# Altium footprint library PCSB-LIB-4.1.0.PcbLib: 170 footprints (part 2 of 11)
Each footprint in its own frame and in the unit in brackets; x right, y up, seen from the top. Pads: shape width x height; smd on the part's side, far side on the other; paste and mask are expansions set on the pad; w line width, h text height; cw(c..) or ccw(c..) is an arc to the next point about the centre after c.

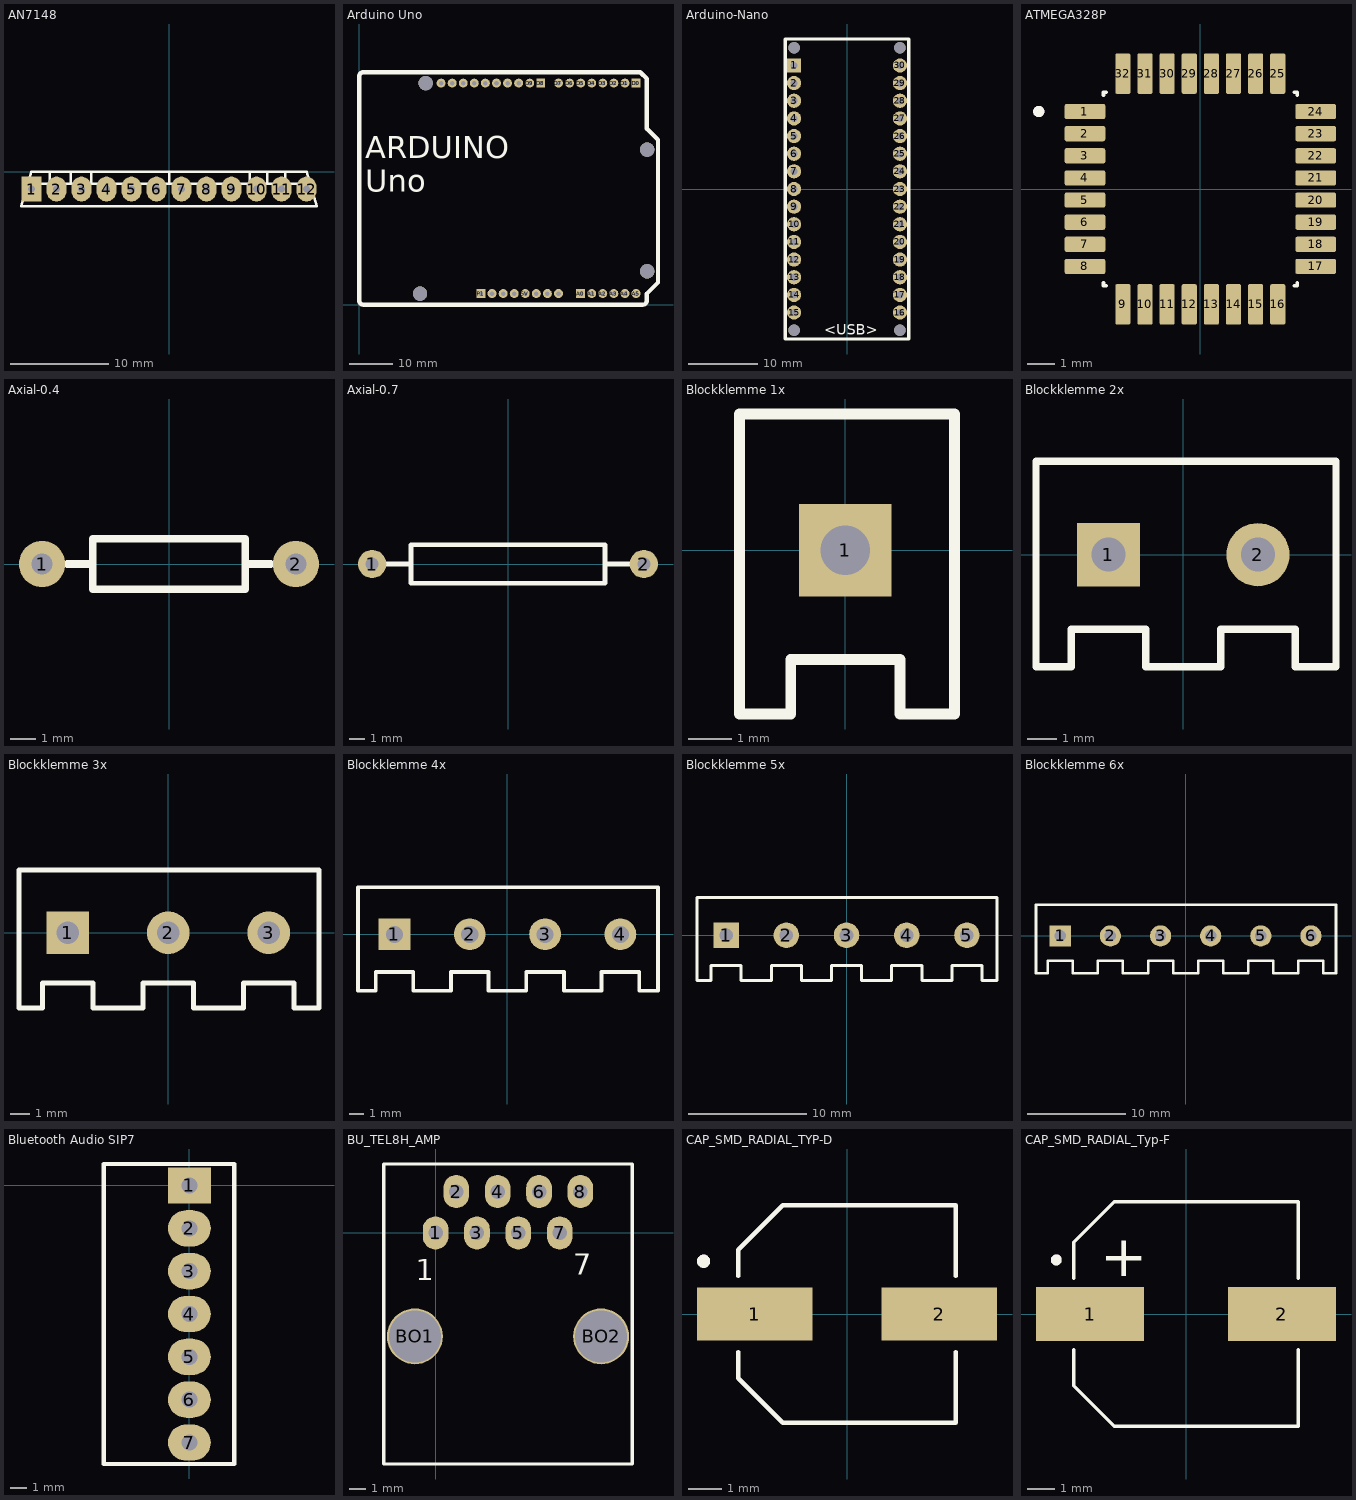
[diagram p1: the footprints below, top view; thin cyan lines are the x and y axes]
## AN7148 [mm]
pads (12):
  rect 2x2.54 hole 0.75: 1(-13.97,-1.753)
  oval 2x2.54 hole 0.75: 2(-11.43,-1.753) 3(-8.89,-1.753) 4(-6.35,-1.753) 5(-3.81,-1.753) 6(-1.27,-1.753) 7(1.27,-1.753) 8(3.81,-1.753) 9(6.35,-1.753) 10(8.89,-1.753) 11(11.43,-1.753) 12(13.97,-1.753)
Top Overlay:
  lines w0.254: -14.343,-1.2 14.343,-1.2 ; -12.1,-1.2 -12.1,0 ; -10,-1.2 -10,0 ; -7.9,-1.2 -7.9,0 ; 0,-1.2 0,0 ; 8.2,-1.2 8.2,0 ; 10,-1.2 10,0 ; 11.8,-1.2 11.8,0 ; -15,-3.5 15,-3.5 14,0 -14,0 -15,-3.5

## Arduino Uno [mm]
pads (36):
  round 2.05 hole 1.05: 3V3(35.56,2.54) 5V(38.1,2.54) A1(53.34,2.54) A2(55.88,2.54) A3(58.42,2.54) A4(60.96,2.54) A4(SDA)(21.336,50.8) A5(63.5,2.54) A5(SCL)(18.796,50.8) AREF(23.876,50.8) D1(60.96,50.8) D2(58.42,50.8) D3(55.88,50.8) D4(53.34,50.8) D5(50.8,50.8) D6(48.26,50.8) D7(45.72,50.8) D9(39.116,50.8) D10(36.576,50.8) D11(34.036,50.8) D12(31.496,50.8) D13(28.956,50.8) GND_1(43.18,2.54) GND_2(40.64,2.54) GND_3(26.416,50.8) IOREF(30.48,2.54) RST(33.02,2.54) VIN(45.72,2.54)
  rect 2.05x2.05 hole 1.05: A0(50.8,2.54) D0(63.5,50.8) D8(41.656,50.8) P1(27.94,2.54)
  round 3.3 hole 3.3 unplated: ""(13.97,2.54) ""(15.24,50.8) ""(66.04,7.62) ""(66.04,35.56)
Top Overlay:
  lines w1: 0,0.993 0,52.283 ; 0,0.993 0.042,0.739 ; 0,0.993 0.042,0.739 ; 0,0.993 0,52.283 ; 0,52.283 0.042,52.558 ; 0,52.283 0.042,52.558 ; 0.042,0.739 0.127,0.506 ; 0.042,0.739 0.127,0.506 ; 0.042,52.558 0.127,52.791 ; 0.042,52.558 0.127,52.791 ; 0.127,0.506 0.296,0.295 ; 0.127,0.506 0.296,0.295 ; 0.127,52.791 0.296,53.002 ; 0.127,52.791 0.296,53.002 ; 0.296,0.295 0.508,0.126 ; 0.296,0.295 0.508,0.126 ; 0.296,53.002 0.508,53.151 ; 0.296,53.002 0.508,53.151 ; 0.508,0.126 0.741,0.041 ; 0.508,0.126 0.741,0.041 ; 0.508,53.151 0.741,53.256 ; 0.508,53.151 0.741,53.256 ; 0.741,0.041 0.994,-0.001 ; 0.741,0.041 0.994,-0.001 ; 0.741,53.256 0.994,53.299 ; 0.741,53.256 0.994,53.299 ; 0.994,-0.001 65.001,-0.001 ; 0.994,-0.001 65.001,-0.001 ; 0.994,53.299 64.472,53.299 ; 0.994,53.299 64.472,53.299 ; 64.472,53.299 65.995,51.775 ; 64.472,53.299 65.995,51.775 ; 65.001,-0.001 65.255,0.041 ; 65.001,-0.001 65.255,0.041 ; 65.255,0.041 65.488,0.126 ; 65.255,0.041 65.488,0.126 ; 65.488,0.126 65.699,0.295 ; 65.488,0.126 65.699,0.295 ; 65.699,0.295 65.869,0.506 ; 65.699,0.295 65.869,0.506 ; 65.869,0.506 65.953,0.739 ; 65.869,0.506 65.953,0.739 ; 65.953,0.739 65.995,0.993 ; 65.953,0.739 65.995,0.993 ; 65.995,0.993 65.995,2.538 ; 65.995,0.993 65.995,2.538 ; 65.995,2.538 68.535,5.077 ; 65.995,2.538 68.535,5.077 ; 65.995,40.349 68.535,37.81 ; 65.995,40.349 65.995,51.775 ; 65.995,40.349 65.995,51.775 ; 65.995,40.349 68.535,37.81 ; 68.535,5.077 68.535,37.81 ; 68.535,5.077 68.535,37.81
  text "ARDUINO  / Uno" at 1.397,25.913 h5.08
Mechanical 15:
  lines w0.05: -0.25,1.003 ccw(c0.932,0.921) 0.747,-0.249 ; 64.989,-0.25 ccw(c64.943,1.057) 66.249,0.989

## Arduino-Nano [mm]
pads (34):
  rect 2.05x2.05 hole 1.05: 1(-7.62,17.78)
  round 2.05 hole 1.05: 2(-7.62,15.24) 3(-7.62,12.7) 4(-7.62,10.16) 5(-7.62,7.62) 6(-7.62,5.08) 7(-7.62,2.54) 8(-7.62,0) 9(-7.62,-2.54) 10(-7.62,-5.08) 11(-7.62,-7.62) 12(-7.62,-10.16) 13(-7.62,-12.7) 14(-7.62,-15.24) 15(-7.62,-17.78) 16(7.62,-17.78) 17(7.62,-15.24) 18(7.62,-12.7) 19(7.62,-10.16) 20(7.62,-7.62) 21(7.62,-5.08) 22(7.62,-2.54) 23(7.62,0) 24(7.62,2.54) 25(7.62,5.08) 26(7.62,7.62) 27(7.62,10.16) 28(7.62,12.7) 29(7.62,15.24) 30(7.62,17.78)
  round 1.651 hole 1.651 unplated: ""(-7.62,-20.32) ""(-7.62,20.32) ""(7.62,-20.32) ""(7.62,20.32)
Top Overlay:
  lines w0.5: -8.89,-21.59 8.89,-21.59 8.89,21.59 -8.89,21.59 -8.89,-21.59
  text "<USB>" at -3.302,-20.955 h1.52

## ATMEGA328P [mm]
height 1.2
pads (32):
  rrect25% 1.47x0.55 smd: 1(-4.17,2.8) 2(-4.17,2) 3(-4.17,1.2) 4(-4.17,0.4) 5(-4.17,-0.4) 6(-4.17,-1.2) 7(-4.17,-2) 8(-4.17,-2.8) 17(4.17,-2.8) 18(4.17,-2) 19(4.17,-1.2) 20(4.17,-0.4) 21(4.17,0.4) 22(4.17,1.2) 23(4.17,2) 24(4.17,2.8)
  rrect25% 0.55x1.47 smd: 9(-2.8,-4.17) 10(-2,-4.17) 11(-1.2,-4.17) 12(-0.4,-4.17) 13(0.4,-4.17) 14(1.2,-4.17) 15(2,-4.17) 16(2.8,-4.17) 25(2.8,4.17) 26(2,4.17) 27(1.2,4.17) 28(0.4,4.17) 29(-0.4,4.17) 30(-1.2,4.17) 31(-2,4.17) 32(-2.8,4.17)
Top Overlay:
  circle w0.2: c-5.84,2.8 r0.1
  lines w0.127: -3.5,-3.395 -3.5,-3.5 -3.395,-3.5 ; -3.5,3.395 -3.5,3.5 -3.395,3.5 ; 3.395,-3.5 3.5,-3.5 3.5,-3.395 ; 3.395,3.5 3.5,3.5 3.5,3.395
Mechanical 13:
  circle w0.2: c-5.84,2.8 r0.1

## Axial-0.4 [mm]
pads (2):
  round 1.85 hole 0.85: 1(-5.08,0) 2(5.08,0)
Top Overlay:
  lines w0.305: -4.064,0 -3.048,0 ; 3.048,0 4.064,0 ; -3.048,-1.016 -3.048,1.016 3.048,1.016 3.048,-1.016 -3.048,-1.016

## Axial-0.7 [mm]
pads (2):
  round 1.85 hole 0.85: 1(-8.89,0) 2(8.89,0)
Top Overlay:
  lines w0.305: -8.89,0 -6.35,0 ; 6.35,0 8.89,0 ; -6.35,-1.27 6.35,-1.27 6.35,1.27 -6.35,1.27 -6.35,-1.27

## Blockklemme 1x [mm]
pads (1):
  rect 2.15x2.15 hole 1.15: 1(0,0)
Top Overlay:
  lines w0.254: -2.46,-3.81 -2.46,2.365 -2.46,3.175 2.54,3.175 2.54,-3.81 1.27,-3.81 1.27,-2.54 -1.27,-2.54 -1.27,-3.81 -2.46,-3.81

## Blockklemme 2x [mm]
pads (2):
  rect 2.15x2.15 hole 1.15: 1(-2.54,0)
  round 2.15 hole 1.15: 2(2.54,0)
Top Overlay:
  lines w0.254: 1.27,-3.81 1.27,-2.54 ; 1.27,-3.81 -1.27,-3.81 -1.27,-2.54 -3.81,-2.54 -3.81,-3.81 -5,-3.81 -5,2.365 -5,3.175 5.19,3.175 5.19,-3.81 3.81,-3.81 ; 1.27,-3.81 1.27,-2.54 ; 1.27,-2.54 3.81,-2.54 ; 3.81,-3.81 3.81,-2.54 ; 3.81,-3.81 3.81,-2.54

## Blockklemme 3x [mm]
pads (3):
  rect 2.15x2.15 hole 1.15: 1(-5.08,0)
  round 2.15 hole 1.15: 2(0,0) 3(5.08,0)
Top Overlay:
  lines w0.254: -1.27,-3.81 -1.27,-2.54 ; -1.27,-3.81 -3.81,-3.81 -3.81,-2.54 -6.35,-2.54 -6.35,-3.81 -7.54,-3.81 -7.54,2.365 -7.54,3.175 2.65,3.175 7.62,3.175 7.62,-3.81 6.35,-3.81 6.35,-2.54 3.81,-2.54 3.81,-3.81 1.27,-3.81 ; -1.27,-3.81 -1.27,-2.54 ; -1.27,-2.54 1.27,-2.54 ; 1.27,-3.81 1.27,-2.54 ; 1.27,-3.81 1.27,-2.54

## Blockklemme 4x [mm]
pads (4):
  rect 2.15x2.15 hole 1.15: 1(-7.62,0)
  round 2.15 hole 1.15: 2(-2.54,0) 3(2.54,0) 4(7.62,0)
Top Overlay:
  lines w0.254: -3.81,-3.81 -3.81,-2.54 ; -3.81,-3.81 -6.35,-3.81 -6.35,-2.54 -8.89,-2.54 -8.89,-3.81 -10.08,-3.81 -10.08,2.365 -10.08,3.175 0.11,3.175 10.16,3.175 10.16,-3.81 8.89,-3.81 8.89,-2.54 6.35,-2.54 6.35,-3.81 3.81,-3.81 3.81,-2.54 1.27,-2.54 1.27,-3.81 -1.27,-3.81 ; -3.81,-3.81 -3.81,-2.54 ; -3.81,-2.54 -1.27,-2.54 ; -1.27,-3.81 -1.27,-2.54 ; -1.27,-3.81 -1.27,-2.54

## Blockklemme 5x [mm]
pads (5):
  rect 2.15x2.15 hole 1.15: 1(-10.16,0)
  round 2.15 hole 1.15: 2(-5.08,0) 3(0,0) 4(5.08,0) 5(10.16,0)
Top Overlay:
  lines w0.254: -6.35,-3.81 -6.35,-2.54 ; -6.35,-3.81 -8.89,-3.81 -8.89,-2.54 -11.43,-2.54 -11.43,-3.81 -12.62,-3.81 -12.62,2.365 -12.62,3.175 -2.43,3.175 12.7,3.175 12.7,-3.81 11.43,-3.81 11.43,-2.54 8.89,-2.54 8.89,-3.81 6.35,-3.81 6.35,-2.54 3.81,-2.54 3.81,-3.81 1.27,-3.81 1.27,-2.54 -1.27,-2.54 -1.27,-3.81 -3.81,-3.81 ; -6.35,-3.81 -6.35,-2.54 ; -6.35,-2.54 -3.81,-2.54 ; -3.81,-3.81 -3.81,-2.54 ; -3.81,-3.81 -3.81,-2.54

## Blockklemme 6x [mm]
pads (6):
  rect 2.15x2.15 hole 1.15: 1(-12.7,0)
  round 2.15 hole 1.15: 2(-7.62,0) 3(-2.54,0) 4(2.54,0) 5(7.62,0) 6(12.7,0)
Top Overlay:
  lines w0.254: -8.89,-3.81 -8.89,-2.54 ; -8.89,-3.81 -11.43,-3.81 -11.43,-2.54 -13.97,-2.54 -13.97,-3.81 -15.16,-3.81 -15.16,2.365 -15.16,3.175 -4.97,3.175 15.24,3.175 15.24,-3.81 13.97,-3.81 13.97,-2.54 11.43,-2.54 11.43,-3.81 8.89,-3.81 8.89,-2.54 6.35,-2.54 6.35,-3.81 3.81,-3.81 3.81,-2.54 1.27,-2.54 1.27,-3.81 -1.27,-3.81 -1.27,-2.54 -3.81,-2.54 -3.81,-3.81 -6.35,-3.81 ; -8.89,-3.81 -8.89,-2.54 ; -8.89,-2.54 -6.35,-2.54 ; -6.35,-3.81 -6.35,-2.54 ; -6.35,-3.81 -6.35,-2.54

## Bluetooth Audio SIP7 [mm]
pads (7):
  rect 2.54x2.15 hole 0.95: 1(0,0)
  oval 2.54x2.15 hole 0.95: 2(0,-2.54) 3(0,-5.08) 4(0,-7.62) 5(0,-10.16) 6(0,-12.7) 7(0,-15.24)
Top Overlay:
  lines w0.254: -5.08,-16.51 2.667,-16.51 2.667,1.27 -5.08,1.27 -5.08,-16.51

## BU_TEL8H_AMP [mil]
pads (10):
  oval 62x80 hole 35: 1(0,0) 2(50,100) 3(100,0) 4(150,100) 5(200,0) 6(250,100) 7(300,0) 8(350,100)
  round 135 hole 125: BO1(-50,-250) BO2(400,-250)
Top Overlay:
  lines w8: -125,-558.33 -125,166.67 475,166.67 475,-558.33 -125,-558.33
  text "1" at -47.84,-114.13 h50
  text "7" at 332.45,-101.06 h50

## CAP_SMD_RADIAL_TYP-D [mm]
pads (2):
  rect 3.5x1.6 smd: 1(-2.8,0) 2(2.8,0)
Top Overlay:
  circle w0.2: c-4.35,1.6 r0.1
  lines w0.127: -3.3,-1.15 -3.3,-1.95 -1.95,-3.3 3.3,-3.3 3.3,-1.15 ; -3.3,1.15 -3.3,1.95 -1.95,3.3 3.3,3.3 3.3,1.15
Mechanical 13:
  circle w0.2: c-4.35,1.6 r0.1

## CAP_SMD_RADIAL_Typ-F [mm]
pads (2):
  rect 4x2 smd: 1(-3.55,0) 2(3.55,0)
Top Overlay:
  circle w0.2: c-4.8,2 r0.1
  lines w0.127: -4.15,-1.32 -4.15,-2.65 -2.65,-4.15 4.15,-4.15 4.15,-1.32 ; -4.15,1.32 -4.15,2.65 -2.65,4.15 4.15,4.15 4.15,1.32
  text "+" at -3.175,1.397 h1.52
Mechanical 13:
  circle w0.2: c-4.8,2 r0.1
3D body "step_temp.STEP": height 0, standoff 0, extent 0,0 0,0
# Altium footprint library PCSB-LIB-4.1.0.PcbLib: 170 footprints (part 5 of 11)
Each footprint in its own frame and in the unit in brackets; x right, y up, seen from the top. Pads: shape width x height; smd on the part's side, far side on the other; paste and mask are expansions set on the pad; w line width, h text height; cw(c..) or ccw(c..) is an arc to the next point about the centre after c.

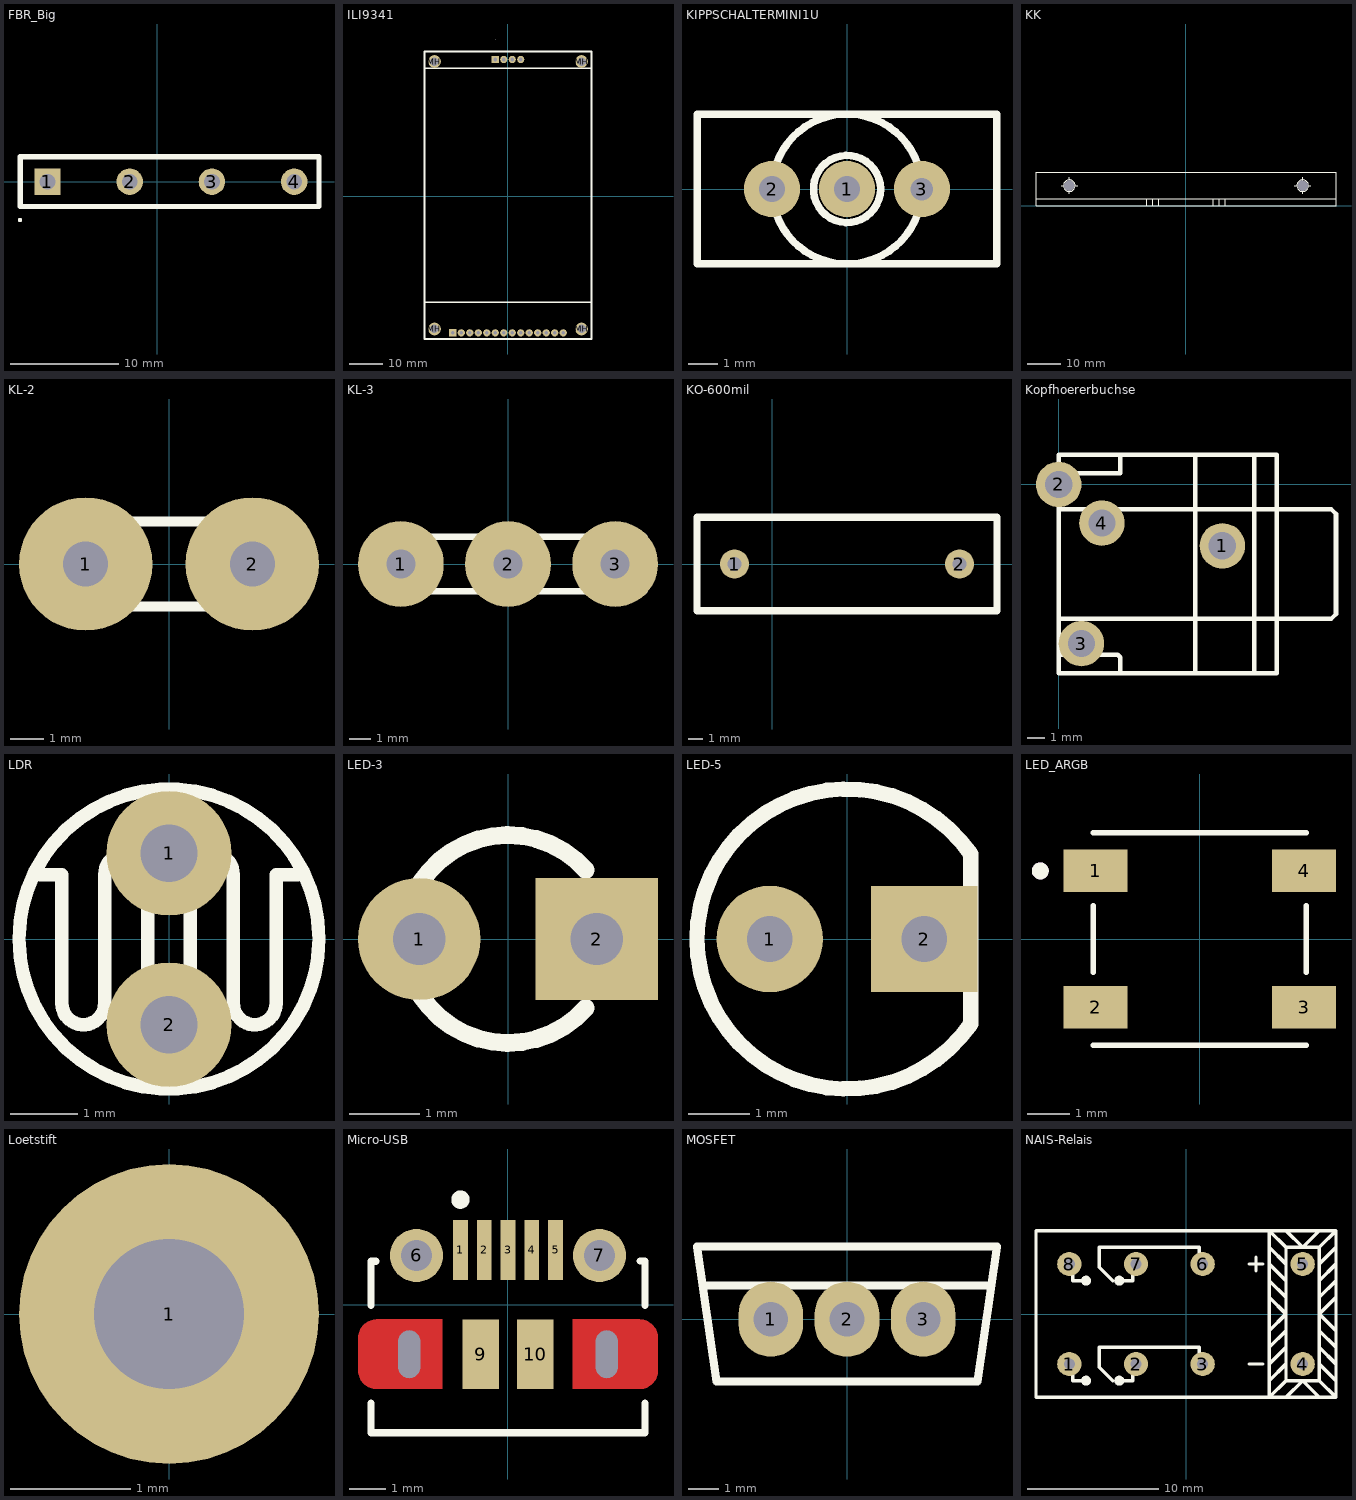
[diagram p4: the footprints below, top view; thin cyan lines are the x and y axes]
## FBR_Big [mm]
height 23
pads (4):
  rect 2.45x2.45 hole 1.45: 1(-10.16,0)
  round 2.45 hole 1.45: 2(-2.54,0) 3(5.08,0) 4(12.7,0)
Top Overlay:
  circle w0.2: c-12.7,-3.556 r0.1
  lines w0.5: -12.7,-2.3 15,-2.3 15,2.3 -12.7,2.3 -12.7,-2.3

## ILI9341 [mm]
pads (22):
  rect 2.15x2.15 hole 1.15: A1(-3.81,40.88) B1(-16.51,-40.88)
  round 2.15 hole 1.15: A2(-1.27,40.88) A3(1.27,40.88) A4(3.81,40.88) B2(-13.97,-40.88) B3(-11.43,-40.88) B4(-8.89,-40.88) B5(-6.35,-40.88) B6(-3.81,-40.88) B7(-1.27,-40.88) B8(1.27,-40.88) B9(3.81,-40.88) B10(6.35,-40.88) B11(8.89,-40.88) B12(11.43,-40.88) B13(13.97,-40.88) B14(16.51,-40.88)
  round 3.81 hole 2.54: MH(-22,-39.73) MH(-22,40.27) MH(22,-39.73) MH(22,40.27)
Top Overlay:
  lines w0.1: -3.81,46.92 cw(c-3.81,46.97) -3.81,47.02 cw(c-3.81,46.97) -3.81,46.92
  lines w0.5: -25,-31.73 25,-31.73 ; -25,38.27 25,38.27 ; -25,-42.73 -25,43.27 25,43.27 25,1.27 25,-42.73 -25,-42.73

## KIPPSCHALTERMINI1U [mil]
pads (3):
  round 75 hole 35: 1(0,0) 2(-100,0)
  round 75 hole 30: 3(100,0)
Top Overlay:
  circle w10: c0,0 r100
  circle w10: c0,0 r44.72
  lines w10: 0,-30 cw(c0,0) 9.49,28.46 ; -200,-100 200,-100 200,100 -200,100 -200,-100

## KK [mm]
pads (2):
  rect 0x0 hole 3.2 unplated: 0(-35,6) 0(35,6)
Top Overlay:
  circle w0.254: c-35,6 r1.75
  circle w0.254: c35,6 r1.75
  lines w0.254: -45,2 45,2 ; -37.5,6 -32.5,6 ; -35,3.5 -35,8.5 ; -11.8,0 -11.8,2 ; -10,0 -10,2 ; -8.2,0 -8.2,2 ; 8.2,0 8.2,2 ; 10,0 10,2 ; 11.8,0 11.8,2 ; 32.5,6 37.5,6 ; 35,3.5 35,8.5 ; -45,0 45,0 45,10 -45,10 -45,0

## KL-2 [mm]
height 10
pads (2):
  round 4 hole 1.35: 1(-2.5,0) 2(2.5,0)
Top Overlay:
  lines w0.3: -3.81,-1.27 -3.81,1.27 3.81,1.27 3.81,-1.27 -3.81,-1.27

## KL-3 [mm]
height 10
pads (3):
  round 4 hole 1.35: 1(-5,0) 2(0,0) 3(5,0)
Top Overlay:
  lines w0.3: -5.715,-1.27 -5.715,1.27 6.35,1.27 6.35,-1.27 -5.715,-1.27

## KO-600mil [mm]
pads (2):
  round 1.95 hole 0.95: 1(-2.54,0) 2(12.7,0)
Top Overlay:
  lines w0.5: -5.08,1.27 -5.08,3.175 15.24,3.175 15.24,-3.175 -5.08,-3.175 -5.08,1.595

## Kopfhoererbuchse [mil]
pads (4):
  round 100 hole 60: 1(360,-135) 2(0,0) 3(50,-350) 4(95,-85)
Top Overlay:
  lines w10: 0,-375 130,-375 135,-380 135,-415 ; 0,-295 480,-295 600,-295 610,-285 610,-65 600,-55 480,-55 0,-55 ; 0,25 135,25 135,65 ; 300,-415 300,65 ; 430,-415 430,65 ; 0,-415 0,65 480,65 480,-415 0,-415

## LDR [mm]
pads (2):
  round 1.85 hole 0.85: 1(0,1.27) 2(0,-1.27)
Top Overlay:
  circle w0.2: c0,0 r2.222
  lines w0.2: -1.905,0.953 -1.587,0.953 -1.587,-0.953 ccw(c-1.27,-0.953) -0.953,-0.953 -0.953,0.953 cw(c-0.635,0.953) -0.318,0.953 -0.318,-0.953 ; 0.318,-0.953 0.318,0.953 cw(c0.635,0.953) 0.953,0.953 0.953,-0.953 ccw(c1.27,-0.953) 1.587,-0.953 1.587,0.953 1.905,0.953
Mechanical 13:
  lines w0.2: -0.318,-0.953 ccw(c0,-0.953) 0.318,-0.953

## LED-3 [mm]
pads (2):
  round 1.75 hole 0.75: 1(-1.27,0)
  rect 1.75x1.75 hole 0.75: 2(1.27,0)
Top Overlay:
  lines w0.254: 1.111,-0.988 cw(c0,0) 1.111,0.988 ; 1.397,-0.508 1.397,0.508

## LED-5 [mm]
pads (2):
  round 1.75 hole 0.75: 1(-1.27,0)
  rect 1.75x1.75 hole 0.75: 2(1.27,0)
Top Overlay:
  lines w0.254: 2.032,-1.397 cw(c0,0) 2.032,1.397 2.032,-1.397

## LED_ARGB [mm]
pads (4):
  rect 1.5x1 smd: 1(-2.45,1.6) 2(-2.45,-1.6) 3(2.45,-1.6) 4(2.45,1.6)
Top Overlay:
  circle w0.2: c-3.75,1.6 r0.1
  lines w0.127: -2.5,-2.5 2.5,-2.5 ; -2.5,-0.787 -2.5,0.787 ; -2.5,2.5 2.5,2.5 ; 2.5,-0.787 2.5,0.787
Mechanical 13:
  circle w0.2: c-3.75,1.6 r0.1

## Loetstift [mm]
pads (1):
  round 2.5 hole 1.25: 1(0,0)

## Micro-USB [mm] "USB, MICRO B, Body 7.491x4.695 mm, Pitch 0.65 mm"
height 2.673
pads (11):
  rect 0.4x1.65 smd: 1(-1.3,1.5) 2(-0.65,1.5) 3(0,1.5) 4(0.65,1.5) 5(1.3,1.5)
  round 1.45 hole 0.85: 6(-2.5,1.35) 7(2.5,1.35)
  rrect50% 0x0 hole 0.6 slot 1.3 at 90 deg: 8(-2.7,-1.35) 11(2.7,-1.35)
  rect 1x1.9 smd: 9(-0.75,-1.35) 10(0.75,-1.35)
Top Layer:
  circle w0.5: c3.6,-0.9 r0.25
  circle w0.5: c3.6,-1.8 r0.25
  circle w0.5: c-3.6,-0.9 r0.25
  circle w0.5: c-3.6,-1.8 r0.25
  region: 3.6,-0.9 3.6,-1.8 4.1,-1.8 4.1,-0.9
  region: 1.775,-0.4 1.775,-2.3 3.6,-2.3 3.6,-0.4
  region: -3.6,-1.8 -3.6,-0.9 -4.1,-0.9 -4.1,-1.8
  region: -1.8,-2.3 -1.8,-0.4 -3.6,-0.4 -3.6,-2.3
Top Overlay:
  circle w0.25: c-1.3,2.875 r0.125
  lines w0.2: -3.745,-2.688 -3.745,-3.5 3.745,-3.5 3.745,-2.688 ; -3.745,-0.012 -3.745,1.195 -3.614,1.195 ; 3.615,1.2 3.745,1.2 3.745,-0.012

## MOSFET [mm]
pads (3):
  oval 2.15x2.5 hole 1.15: 1(-2.54,0) 2(0,0) 3(2.54,0)
Top Overlay:
  lines w0.254: -4.812,1.125 4.808,1.125 ; -5,2.425 0,2.425 5,2.425 4.35,-2.075 0,-2.075 -4.35,-2.075 -5,2.425

## NAIS-Relais [mm]
pads (8):
  round 1.85 hole 0.85: 1(-8.89,-3.81) 2(-3.81,-3.81) 3(1.27,-3.81) 4(8.89,-3.81) 5(8.89,3.81) 6(1.27,3.81) 7(-3.81,3.81) 8(-8.89,3.81)
Top Overlay:
  circle w0.254: c-7.62,-5.08 r0.254
  circle w0.254: c-5.08,-5.08 r0.254
  circle w0.254: c-7.62,2.54 r0.254
  circle w0.254: c-5.08,2.54 r0.254
  region: -7.874,-4.826 -7.366,-4.826 -7.366,-5.334 -7.874,-5.334
  region: -5.334,-4.826 -4.826,-4.826 -4.826,-5.334 -5.334,-5.334
  region: -5.232,2.769 -4.877,2.769 -4.877,2.362 -4.928,2.311 -5.258,2.311 -5.258,2.743
  region: -7.772,2.769 -7.747,2.743 -7.442,2.743 -7.442,2.388 -7.493,2.337 -7.671,2.337 -7.671,2.616 -7.798,2.743
  region: -7.366,2.54 -7.62,2.54 -7.595,2.515 -7.595,2.286 -7.62,2.286 -7.671,2.337 -7.62,2.388 -7.62,2.591 -7.493,2.464 -7.493,2.337
  lines w0.254: -8.636,-4.572 -8.636,-5.08 -7.62,-5.08 ; -8.636,3.048 -8.636,2.54 -7.62,2.54 ; -5.588,-5.08 -6.604,-4.064 -6.604,-3.048 -6.604,-2.54 1.016,-2.54 1.016,-3.048 ; -5.588,2.54 -6.604,3.556 -6.604,4.572 -6.604,5.08 1.016,5.08 1.016,4.572 ; -5.08,-5.08 -4.064,-5.08 -4.064,-4.572 ; -5.08,2.54 -4.064,2.54 -4.064,3.048 ; 4.826,-3.81 5.842,-3.81 ; 4.826,3.81 5.842,3.81 ; 5.334,3.302 5.334,4.318 ; 7.62,-3.81 6.35,-5.08 6.35,-3.81 7.62,-2.54 7.62,-1.27 6.35,-2.54 6.35,-1.27 7.62,0 6.35,1.27 6.35,2.54 7.62,1.27 7.62,2.54 6.35,3.81 6.35,5.08 7.62,3.81 ; 10.16,-6.35 8.89,-5.08 7.62,-6.35 6.35,-6.35 ; 10.16,3.81 11.43,5.08 11.43,3.81 10.16,2.54 10.16,1.27 11.43,2.54 11.43,1.27 10.16,0 ; 10.16,6.35 8.89,5.08 7.62,6.35 6.35,6.35 ; 11.43,0 11.43,-1.27 ; 6.35,-6.35 7.62,-5.08 ; 6.35,-6.35 6.35,6.35 ; 6.35,6.35 7.62,5.08 ; 7.62,-5.08 10.16,-5.08 ; 7.62,-5.08 7.62,5.08 ; 7.62,5.08 10.16,5.08 ; 10.16,-5.08 11.43,-6.35 ; 10.16,-5.08 10.16,5.08 ; 10.16,0 11.43,-1.27 ; 10.16,0 10.16,-1.27 11.43,-2.54 11.43,-1.27 ; 10.16,5.08 11.43,6.35 ; 11.43,-6.35 11.43,6.35 ; 11.43,-6.35 -11.43,-6.35 -11.43,6.35 11.43,6.35 ; 10.16,-3.81 11.43,-5.08 11.43,-3.81 10.16,-2.54 10.16,-3.81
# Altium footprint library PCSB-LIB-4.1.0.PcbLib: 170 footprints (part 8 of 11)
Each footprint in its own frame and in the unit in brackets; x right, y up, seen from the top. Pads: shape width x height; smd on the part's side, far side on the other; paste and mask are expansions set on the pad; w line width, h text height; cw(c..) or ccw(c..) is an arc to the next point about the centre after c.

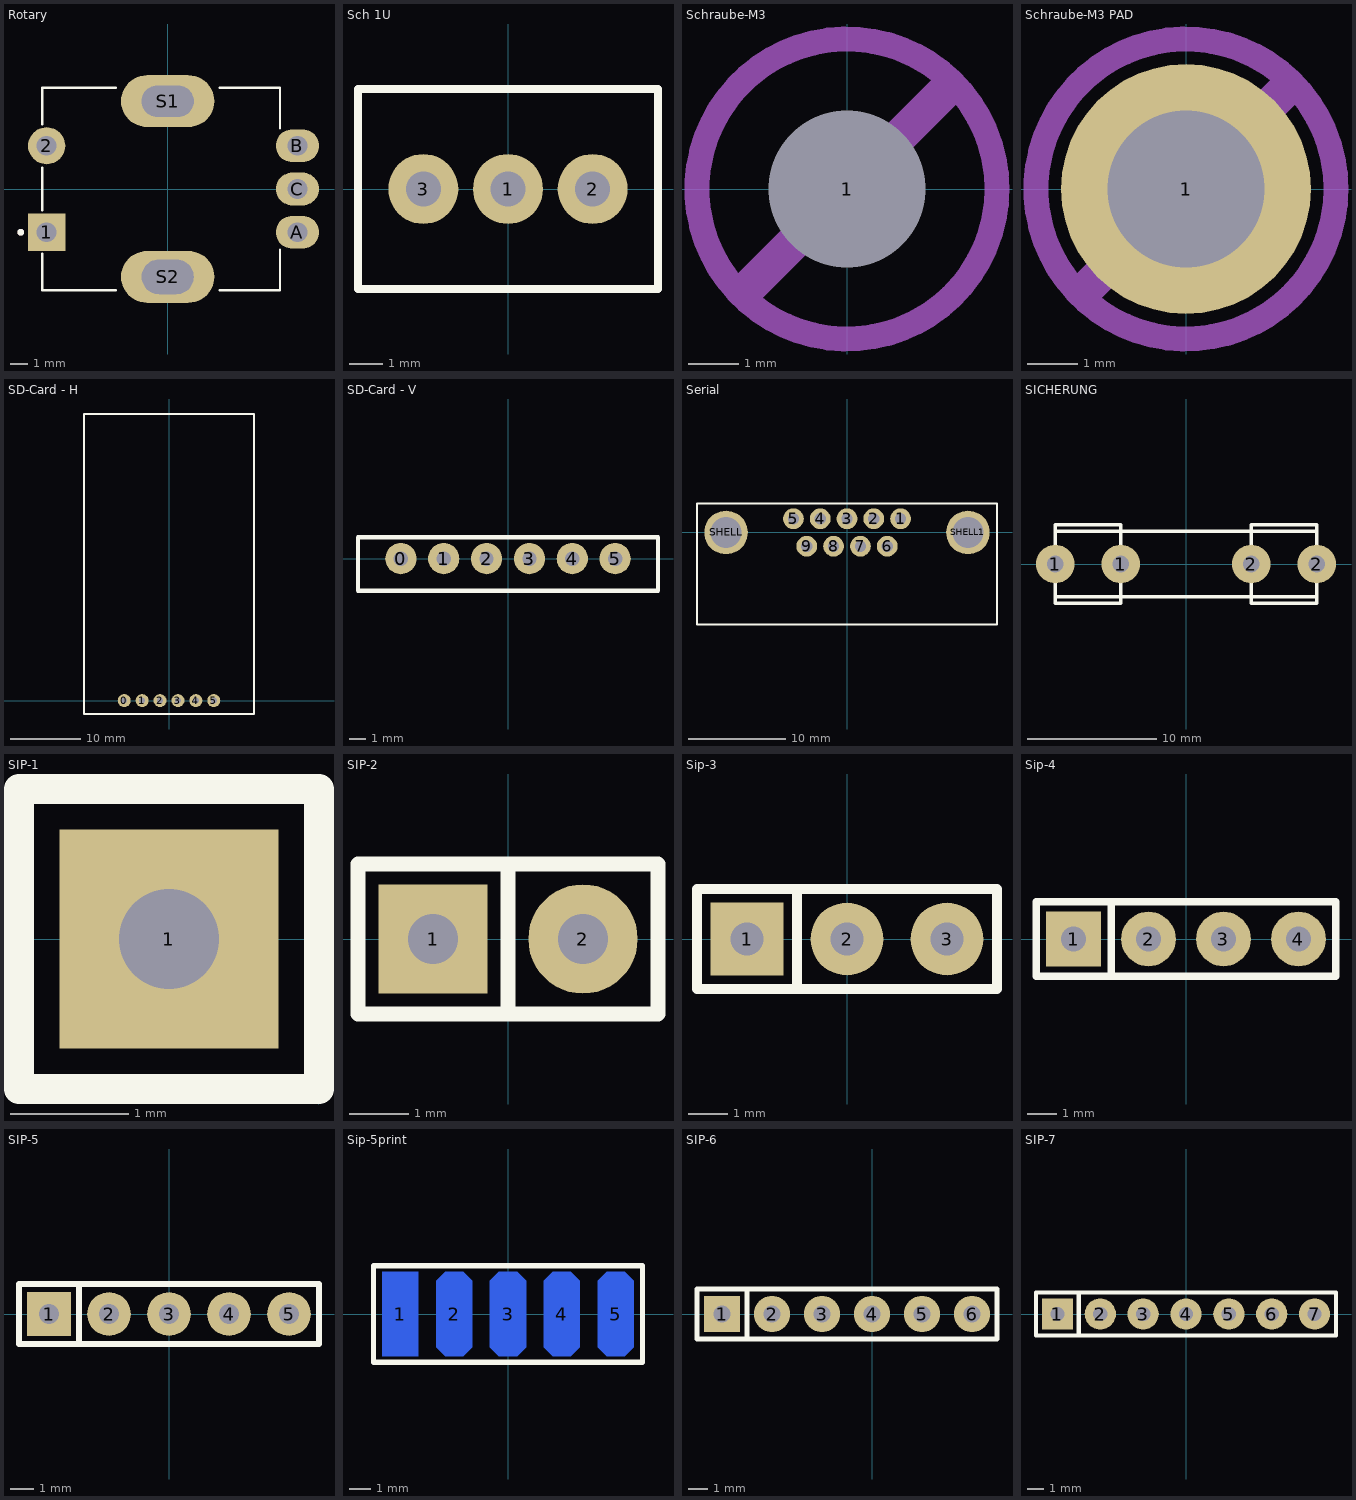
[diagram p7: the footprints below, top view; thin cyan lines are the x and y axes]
## Rotary [mm]
pads (7):
  rect 2.15x2.15 hole 1.15: 1(-7,-2.5)
  round 2.15 hole 1.15: 2(-7,2.5)
  oval 2.5x1.9 hole 1.15: A(7.5,-2.5) B(7.5,2.5) C(7.5,0)
  oval 5.4x3 hole 1.8 slot 3 at 0 deg: S1(0,5.08)
  oval 5.4x3 hole 2 slot 3 at 0 deg: S2(0,-5.08)
Top Overlay:
  circle w0.2: c-8.5,-2.5 r0.1
  lines w0.127: -7.25,-3.75 -7.25,-5.85 -3,-5.85 ; -7.25,-1.25 -7.25,1.25 ; -7.25,3.75 -7.25,5.85 -3,5.85 ; 3,-5.85 6.5,-5.85 6.5,-3.5 ; 3,5.85 6.5,5.85 6.5,3.5
Mechanical 13:
  circle w0.2: c-8.5,-2.5 r0.1

## Sch 1U [mm]
pads (3):
  round 2.1 hole 1.05: 1(0,0) 2(2.54,0) 3(-2.54,0)
Top Overlay:
  lines w0.254: -4.5,-3 -4.5,3 4.5,3 4.5,-3 -4.5,-3

## Schraube-M3 [mm] "Befestigungsschraube für Prints"
pads (1):
  round 0.75 hole 3.15 unplated: 1(0,0)
Mechanical 1:
  circle w0.5: c0,0 r3
  lines w0.7: -2,-2 2,2

## Schraube-M3 PAD [mm] "Befestigungsschraube für Prints"
pads (1):
  round 5 hole 3.15 unplated: 1(0,0)
Mechanical 1:
  circle w0.5: c0,0 r3
  lines w0.7: -2,-2 2,2

## SD-Card - H [mm]
pads (6):
  round 1.85 hole 0.85: 0(-6.35,0) 1(-3.81,0) 2(-1.27,0) 3(1.27,0) 4(3.81,0) 5(6.35,0)
Top Overlay:
  lines w0.254: -12.065,-1.905 12.065,-1.905 12.065,40.64 -12.065,40.64 -12.065,-1.905

## SD-Card - V [mm]
pads (6):
  round 1.85 hole 0.85: 0(-6.35,0) 1(-3.81,0) 2(-1.27,0) 3(1.27,0) 4(3.81,0) 5(6.35,0)
Top Overlay:
  lines w0.254: -8.89,-1.905 8.89,-1.905 8.89,1.27 -8.89,1.27 -8.89,-1.905

## Serial [mm]
pads (11):
  round 2.15 hole 1.15: 1(5.54,1.42) 2(2.77,1.42) 3(0,1.42) 4(-2.77,1.42) 5(-5.54,1.42) 6(4.155,-1.42) 7(1.385,-1.42) 8(-1.385,-1.42) 9(-4.155,-1.42)
  round 4.5 hole 3.2: SHELL(-12.5,0) SHELL1(12.5,0)
Top Overlay:
  lines w0.2: -15.5,-9.52 -15.5,3 15.5,3 15.5,-9.52 -15.5,-9.52

## SICHERUNG [mm]
pads (4):
  round 3 hole 1.3: 1(-10.163,0.008) 1(-5.083,0.008) 2(5.077,0.008) 2(10.157,0.008)
Top Overlay:
  lines w0.254: -10.163,-2.532 -10.163,-3.04 -5.083,-3.04 -5.083,-2.532 -5.083,2.548 -5.083,3.056 -10.163,3.056 -10.163,2.548 ; -10.163,-2.532 10.157,-2.532 ; -10.163,-2.532 -10.163,2.548 ; -10.163,2.548 10.157,2.548 ; 10.157,-2.532 10.157,-3.04 5.077,-3.04 5.077,-2.532 5.077,2.548 5.077,3.056 10.157,3.056 10.157,2.548 ; 10.157,-2.532 10.157,2.548

## SIP-1 [mm]
pads (1):
  rect 1.85x1.85 hole 0.85: 1(-1.27,0)
Top Overlay:
  lines w0.254: -2.54,-1.27 -2.54,1.27 0,1.27 0,-1.27 -2.54,-1.27

## SIP-2 [mm]
pads (2):
  rect 1.85x1.85 hole 0.85: 1(-1.27,0)
  round 1.85 hole 0.85: 2(1.27,0)
Top Overlay:
  lines w0.254: 0,-1.27 0,1.27 ; -2.54,-1.27 2.54,-1.27 2.54,1.27 -2.54,1.27 -2.54,-1.27

## Sip-3 [mm]
pads (3):
  rect 1.85x1.85 hole 0.85: 1(-2.54,0)
  round 1.85 hole 0.85: 2(0,0) 3(2.54,0)
Top Overlay:
  lines w0.254: -1.27,-1.27 -1.27,1.27 ; -3.81,-1.27 3.81,-1.27 3.81,1.27 -3.81,1.27 -3.81,-1.27

## Sip-4 [mm]
pads (4):
  rect 1.85x1.85 hole 0.85: 1(-3.81,0)
  round 1.85 hole 0.85: 2(-1.27,0) 3(1.27,0) 4(3.81,0)
Top Overlay:
  lines w0.254: -2.54,-1.27 -2.54,1.27 ; -5.08,-1.27 5.08,-1.27 5.08,1.27 -5.08,1.27 -5.08,-1.27

## SIP-5 [mm]
pads (5):
  rect 1.85x1.85 hole 0.85: 1(-5.08,0)
  round 1.85 hole 0.85: 2(-2.54,0) 3(0,0) 4(2.54,0) 5(5.08,0)
Top Overlay:
  lines w0.254: -3.81,-1.27 -3.81,1.27 ; -6.35,-1.27 6.35,-1.27 6.35,1.27 -6.35,1.27 -6.35,-1.27

## Sip-5print [mm]
pads (5):
  rect 1.7x4 smd far side: 1(-5.08,0)
  oct 1.7x4 smd far side: 2(-2.54,0) 3(0,0) 4(2.54,0) 5(5.08,0)
Top Overlay:
  lines w0.254: -6.35,-2.286 6.35,-2.286 6.35,2.286 -6.35,2.286 -6.35,-2.286

## SIP-6 [mm]
pads (6):
  rect 1.85x1.85 hole 0.85: 1(-7.62,0)
  round 1.85 hole 0.85: 2(-5.08,0) 3(-2.54,0) 4(0,0) 5(2.54,0) 6(5.08,0)
Top Overlay:
  lines w0.254: -6.35,-1.27 -6.35,1.27 ; -8.89,-1.27 6.35,-1.27 6.35,1.27 -8.89,1.27 -8.89,-1.27

## SIP-7 [mm]
pads (7):
  rect 1.85x1.85 hole 0.85: 1(-7.62,0)
  round 1.85 hole 0.85: 2(-5.08,0) 3(-2.54,0) 4(0,0) 5(2.54,0) 6(5.08,0) 7(7.62,0)
Top Overlay:
  lines w0.254: -6.35,-1.27 -6.35,1.27 ; -8.89,-1.27 8.89,-1.27 8.89,1.27 -8.89,1.27 -8.89,-1.27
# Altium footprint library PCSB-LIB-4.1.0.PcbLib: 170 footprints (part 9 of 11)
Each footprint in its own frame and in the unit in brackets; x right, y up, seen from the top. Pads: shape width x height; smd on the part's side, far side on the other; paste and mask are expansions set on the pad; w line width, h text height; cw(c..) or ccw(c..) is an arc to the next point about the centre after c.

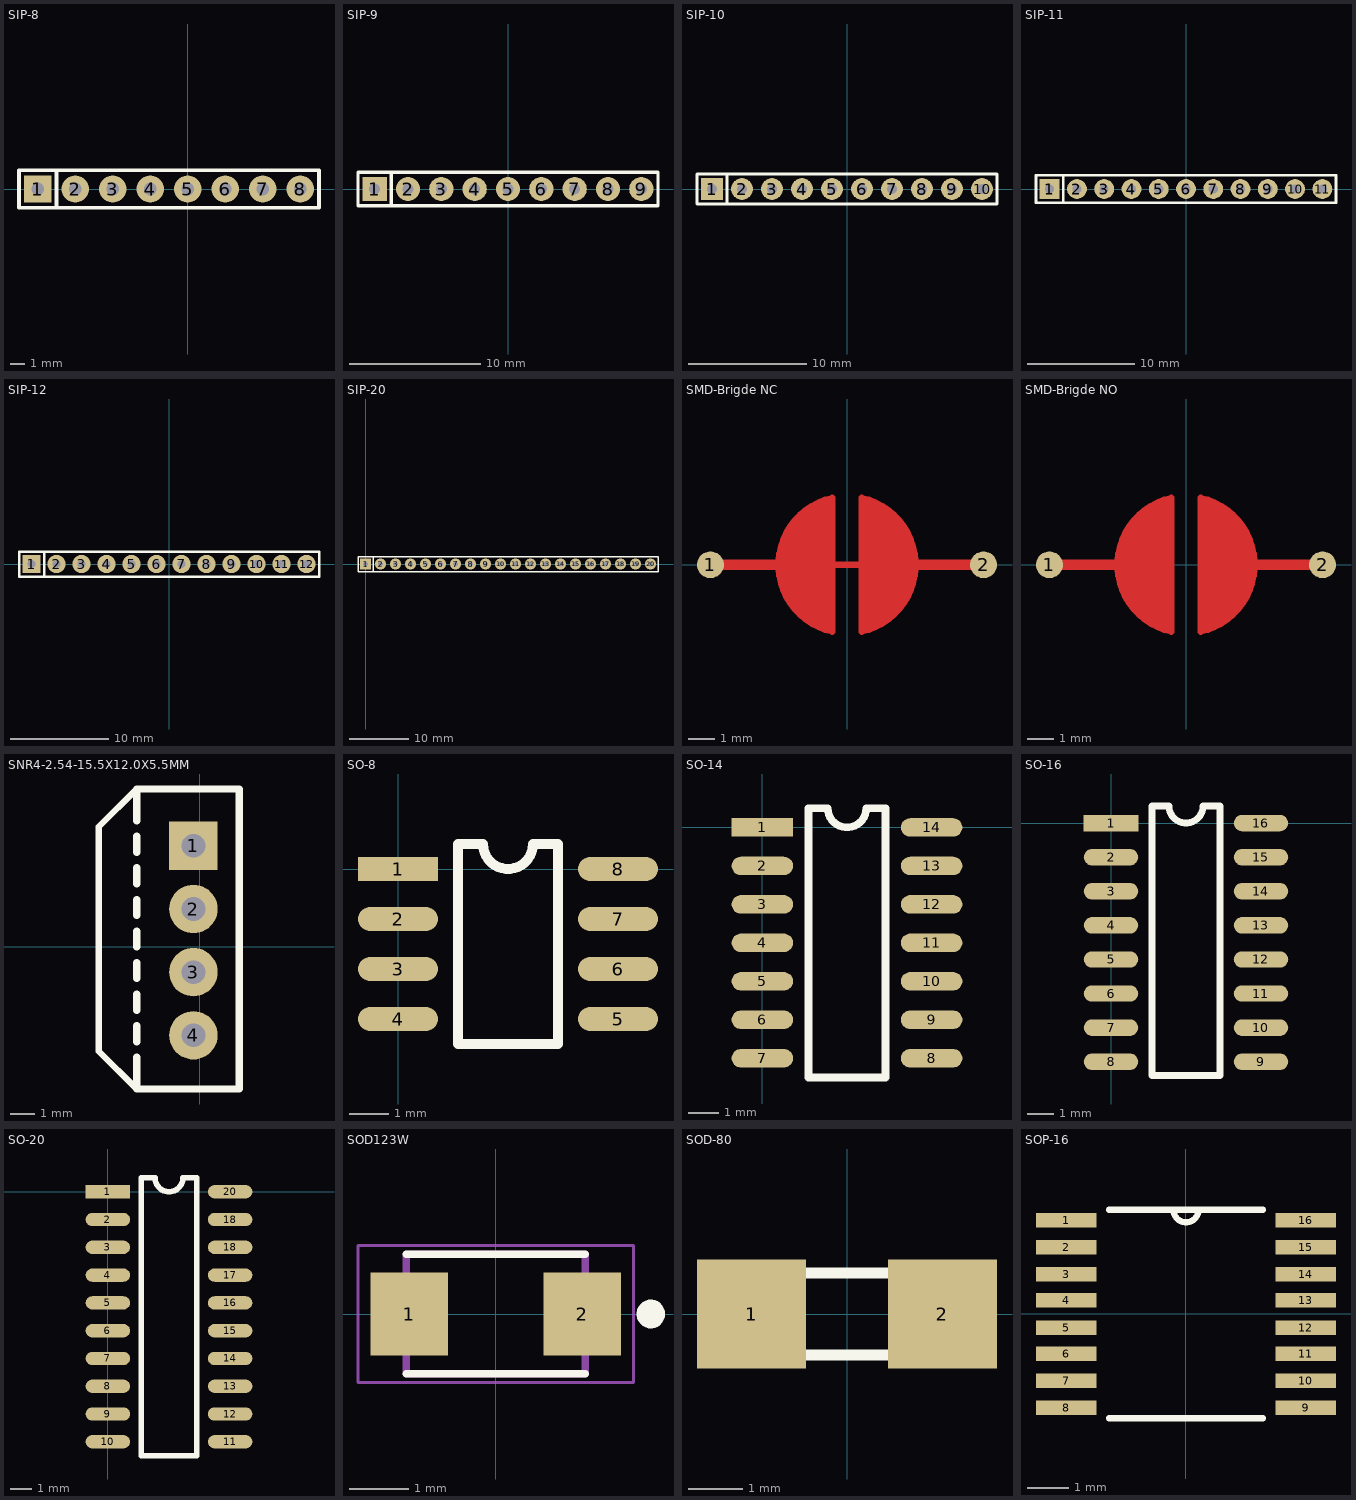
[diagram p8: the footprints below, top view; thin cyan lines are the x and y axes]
## SIP-8 [mm]
pads (8):
  rect 1.85x1.85 hole 0.85: 1(-10.16,0)
  round 1.85 hole 0.85: 2(-7.62,0) 3(-5.08,0) 4(-2.54,0) 5(0,0) 6(2.54,0) 7(5.08,0) 8(7.62,0)
Top Overlay:
  lines w0.254: -8.89,-1.27 -8.89,1.27 ; -11.43,-1.27 -11.43,1.27 8.89,1.27 8.89,-1.27 -11.43,-1.27

## SIP-9 [mm]
pads (9):
  rect 1.85x1.85 hole 0.85: 1(-10.16,0)
  round 1.85 hole 0.85: 2(-7.62,0) 3(-5.08,0) 4(-2.54,0) 5(0,0) 6(2.54,0) 7(5.08,0) 8(7.62,0) 9(10.16,0)
Top Overlay:
  lines w0.254: -8.89,-1.27 -8.89,1.27 ; -11.43,-1.27 11.43,-1.27 11.43,1.27 -11.43,1.27 -11.43,-1.27

## SIP-10 [mm]
pads (10):
  rect 1.85x1.85 hole 0.85: 1(-11.43,0)
  round 1.85 hole 0.85: 2(-8.89,0) 3(-6.35,0) 4(-3.81,0) 5(-1.27,0) 6(1.27,0) 7(3.81,0) 8(6.35,0) 9(8.89,0) 10(11.43,0)
Top Overlay:
  lines w0.254: -10.16,-1.27 -10.16,1.27 ; -12.7,-1.27 12.7,-1.27 12.7,1.27 -12.7,1.27 -12.7,-1.27

## SIP-11 [mm]
pads (11):
  rect 1.85x1.85 hole 0.85: 1(-12.7,0)
  round 1.85 hole 0.85: 2(-10.16,0) 3(-7.62,0) 4(-5.08,0) 5(-2.54,0) 6(0,0) 7(2.54,0) 8(5.08,0) 9(7.62,0) 10(10.16,0) 11(12.7,0)
Top Overlay:
  lines w0.254: -11.43,-1.27 -11.43,1.27 ; -13.97,-1.27 -13.97,1.27 13.97,1.27 13.97,-1.27 -13.97,-1.27

## SIP-12 [mm]
pads (12):
  rect 1.85x1.85 hole 0.85: 1(-13.97,0)
  round 1.85 hole 0.85: 2(-11.43,0) 3(-8.89,0) 4(-6.35,0) 5(-3.81,0) 6(-1.27,0) 7(1.27,0) 8(3.81,0) 9(6.35,0) 10(8.89,0) 11(11.43,0) 12(13.97,0)
Top Overlay:
  lines w0.254: -12.7,-1.27 -12.7,1.27 ; -15.24,-1.27 -15.24,1.27 15.24,1.27 15.24,-1.27 -15.24,-1.27

## SIP-20 [mm]
pads (20):
  rect 1.85x1.85 hole 0.85: 1(0,0)
  round 1.85 hole 0.85: 2(2.54,0) 3(5.08,0) 4(7.62,0) 5(10.16,0) 6(12.7,0) 7(15.24,0) 8(17.78,0) 9(20.32,0) 10(22.86,0) 11(25.4,0) 12(27.94,0) 13(30.48,0) 14(33.02,0) 15(35.56,0) 16(38.1,0) 17(40.64,0) 18(43.18,0) 19(45.72,0) 20(48.26,0)
Top Overlay:
  lines w0.254: 1.27,-1.27 1.27,1.27 ; -1.27,-1.27 -1.27,1.27 49.53,1.27 49.53,-1.27 -1.27,-1.27

## SMD-Brigde NC [mm]
pads (2):
  round 1 smd: 1(-5.08,0) 2(5.08,0)
Top Layer:
  region: 0.551,2.48 0.551,-2.48 0.618,-2.413 1.016,-2.413 1.524,-1.905 1.651,-1.905 2.159,-1.397 2.159,-1.143 2.54,-0.762 2.54,0.762 2.159,1.143 2.159,1.397 1.27,2.286 1.016,2.286 0.762,2.54 0.702,2.48
  region: -0.551,-2.48 -0.551,2.48 -0.618,2.413 -1.016,2.413 -1.524,1.905 -1.651,1.905 -2.159,1.397 -2.159,1.143 -2.54,0.762 -2.54,-0.762 -2.159,-1.143 -2.159,-1.397 -1.27,-2.286 -1.016,-2.286 -0.762,-2.54 -0.702,-2.48
  lines w0.254: -0.762,0 0.762,0 ; -0.551,-2.48 cw(c0,0) -0.551,2.48 -0.551,-2.48 ; 0.551,-2.48 ccw(c0,0) 0.551,2.48 0.551,-2.48
  lines w0.4: -5.08,0 -2.032,0 ; 2.032,0 5.08,0
Top Solder:
  circle w1: c0,0 r2.736
  region: 1.27,2.794 3,1.064 3,-1 1.333,-2.667 -1.397,-2.667 -2.794,-1.27 -2.794,1.206 -1.206,2.794 0,2.794

## SMD-Brigde NO [mm]
pads (2):
  round 1 smd: 1(-5.08,0) 2(5.08,0)
Top Layer:
  region: 0.551,2.48 0.551,-2.48 0.618,-2.413 1.016,-2.413 1.524,-1.905 1.651,-1.905 2.159,-1.397 2.159,-1.143 2.54,-0.762 2.54,0.762 2.159,1.143 2.159,1.397 1.27,2.286 1.016,2.286 0.762,2.54 0.702,2.48
  region: -0.551,-2.48 -0.551,2.48 -0.618,2.413 -1.016,2.413 -1.524,1.905 -1.651,1.905 -2.159,1.397 -2.159,1.143 -2.54,0.762 -2.54,-0.762 -2.159,-1.143 -2.159,-1.397 -1.27,-2.286 -1.016,-2.286 -0.762,-2.54 -0.702,-2.48
  lines w0.254: -0.551,-2.48 cw(c0,0) -0.551,2.48 -0.551,-2.48 ; 0.551,-2.48 ccw(c0,0) 0.551,2.48 0.551,-2.48
  lines w0.4: -5.08,0 -2.032,0 ; 2.032,0 5.08,0
Top Solder:
  circle w1: c0,0 r2.736
  region: 1.143,2.794 2.921,1.016 2.921,-1.016 1.27,-2.667 -1.397,-2.667 -2.794,-1.27 -2.794,1.397 -1.397,2.794 0,2.794

## SNR4-2.54-15.5X12.0X5.5MM [mm]
pads (4):
  rect 1.95x1.95 hole 0.95: 1(-0.254,4.064)
  round 1.95 hole 0.95: 2(-0.254,1.524) 3(-0.254,-1.016) 4(-0.254,-3.556)
Top Overlay:
  lines w0.254: -2.54,-5.715 -4.064,-4.191 -4.064,4.826 -2.54,6.35
  lines w0.3: -2.54,-4.445 -2.54,-5.715 1.59,-5.715 1.59,6.35 -2.54,6.35 -2.54,5.08 ; -2.54,-3.81 -2.54,-3.175 ; -2.54,-2.54 -2.54,-1.905 ; -2.54,-1.27 -2.54,-0.635 ; -2.54,0 -2.54,0.635 ; -2.54,1.27 -2.54,1.905 ; -2.54,2.54 -2.54,3.175 ; -2.54,3.81 -2.54,4.445

## SO-8 [mil]
pads (8):
  rect 80x24 smd: 1(0,0)
  oval 80x24 smd: 2(0,-50) 3(0,-100) 4(0,-150) 5(220,-150) 6(220,-100) 7(220,-50) 8(220,0)
Top Overlay:
  lines w10: 60,-175 160,-175 160,25 135,25 cw(c110,25) 85,25 60,25 60,-175

## SO-14 [mil]
pads (14):
  rect 80x24 smd: 1(0,0)
  oval 80x24 smd: 2(0,-50) 3(0,-100) 4(0,-150) 5(0,-200) 6(0,-250) 7(0,-300) 8(220,-300) 9(220,-250) 10(220,-200) 11(220,-150) 12(220,-100) 13(220,-50) 14(220,0)
Top Overlay:
  lines w10: 60,-325 160,-325 160,25 135,25 cw(c110,25) 85,25 60,25 60,-325

## SO-16 [mil]
pads (16):
  rect 80x24 smd: 1(0,0)
  oval 80x24 smd: 2(0,-50) 3(0,-100) 4(0,-150) 5(0,-200) 6(0,-250) 7(0,-300) 8(0,-350) 9(220,-350) 10(220,-300) 11(220,-250) 12(220,-200) 13(220,-150) 14(220,-100) 15(220,-50) 16(220,0)
Top Overlay:
  lines w10: 60,-370 160,-370 160,25 135,25 cw(c110,25) 85,25 60,25 60,-370

## SO-20 [mil]
pads (20):
  rect 80x24 smd: 1(0,0)
  oval 80x24 smd: 2(0,-50) 3(0,-100) 4(0,-150) 5(0,-200) 6(0,-250) 7(0,-300) 8(0,-350) 9(0,-400) 10(0,-450) 11(220,-450) 12(220,-400) 13(220,-350) 14(220,-300) 15(220,-250) 16(220,-200) 17(220,-150) 18(220,-100) 18(220,-50) 20(220,0)
Top Overlay:
  lines w10: 60,-475 60,25 85,25 ccw(c110,25) 135,25 160,25 160,-475 60,-475

## SOD123W [mm]
pads (2):
  rect 1.3x1.4 smd: 1(-1.45,0) 2(1.45,0)
Top Overlay:
  circle w0.24: c2.6,0 r0.12
  lines w0.127: -1.5,-1 1.5,-1 ; -1.5,1 1.5,1
Mechanical 13:
  lines w0.127: -1.5,-1 1.5,-1 1.5,1 -1.5,1 -1.5,-1
Mechanical 15:
  lines w0.05: -2.31,-1.15 -2.31,1.15 2.31,1.15 2.31,-1.15 -2.31,-1.15

## SOD-80 [mm]
height 1.5
pads (2):
  rect 2x2 smd: 1(-1.75,0) 2(1.75,0)
Top Overlay:
  lines w0.2: 1,-0.75 1,0.75 ; -1.75,-0.75 1.75,-0.75 1.75,0.75 -1.75,0.75 -1.75,-0.75

## SOP-16 [mil]
pads (16):
  rect 58x14 smd: 1(-115,90) 2(-115,64) 3(-115,38) 4(-115,13) 5(-115,-13) 6(-115,-38) 7(-115,-64) 8(-115,-90) 9(115,-90) 10(115,-64) 11(115,-38) 12(115,-13) 13(115,13) 14(115,38) 15(115,64) 16(115,90)
Top Overlay:
  lines w6: -74,-100 74,-100 ; -74,100 -12,100 ; 74,100 12,100 ; -12,100 ccw(c0,100) 12,100 ; -12,100 12,100
Mechanical 13:
  lines w0: -12,100 ccw(c0,100) 12,100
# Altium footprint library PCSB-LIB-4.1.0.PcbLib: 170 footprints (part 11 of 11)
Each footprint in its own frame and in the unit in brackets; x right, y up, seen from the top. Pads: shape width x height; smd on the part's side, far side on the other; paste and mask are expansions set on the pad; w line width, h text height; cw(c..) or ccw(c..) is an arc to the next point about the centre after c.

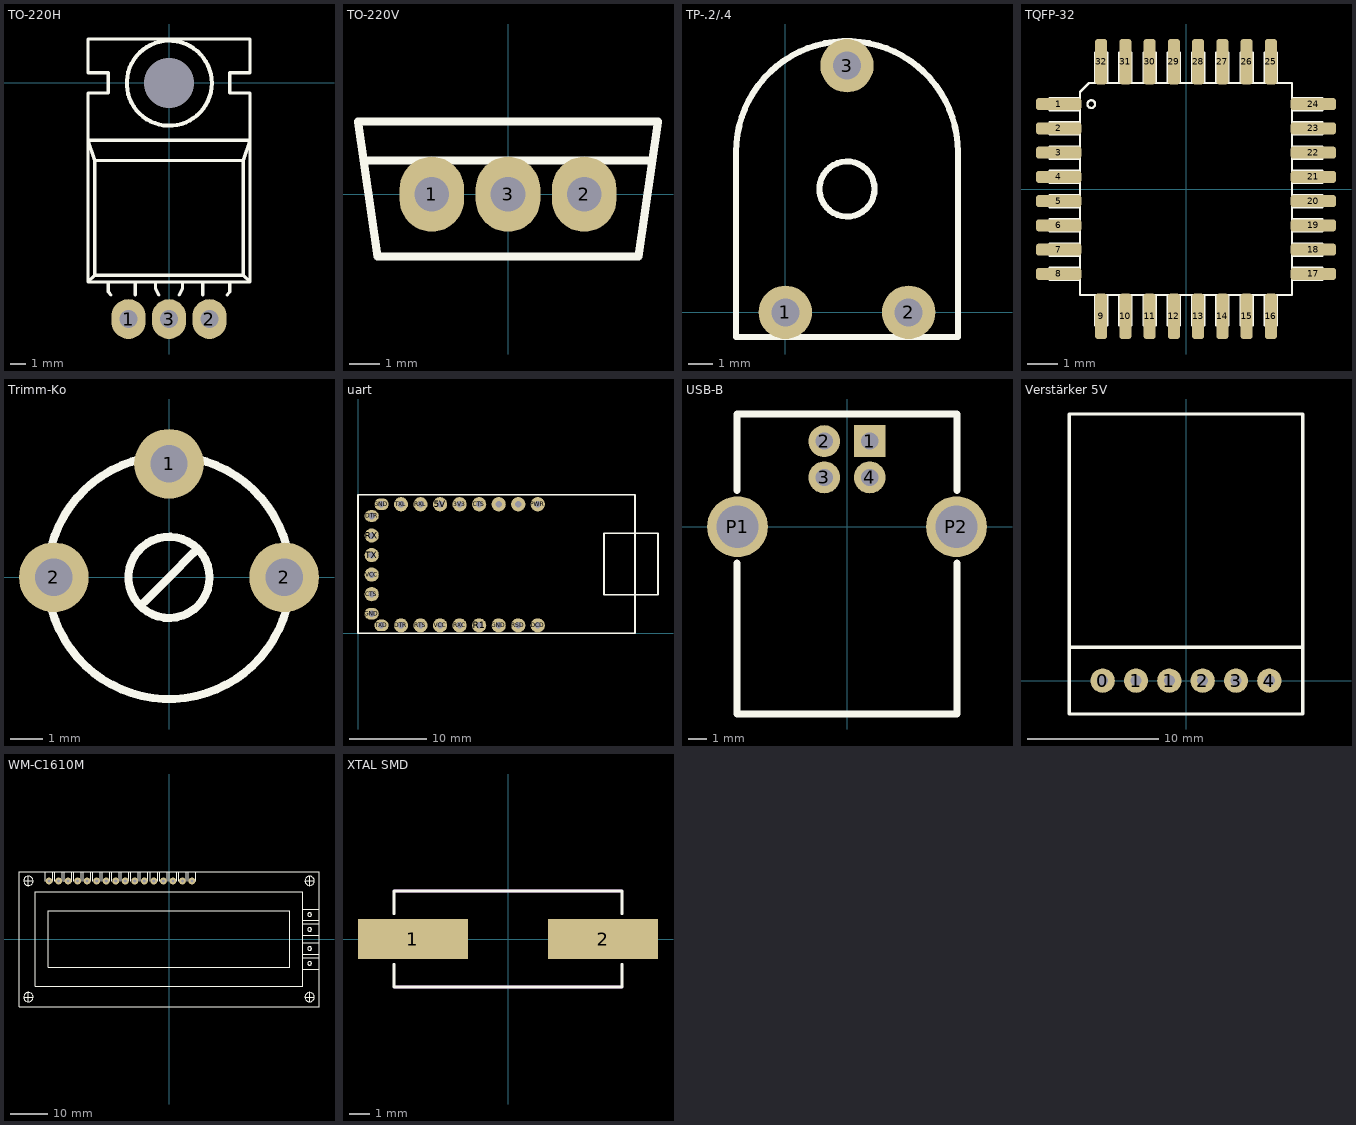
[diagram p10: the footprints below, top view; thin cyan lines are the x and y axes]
## TO-220H [mm]
pads (4):
  round 0 hole 3.15: 0(0,0)
  oval 2.15x2.5 hole 1.15: 1(-2.54,-14.817) 2(2.54,-14.817) 3(0,-14.817)
Top Overlay:
  circle w0.254: c0.017,-0.02 r2.667
  lines w0.2: -3.81,-13.123 -3.81,-12.488 ; -3.762,-13.155 -3.647,-13.317 ; -2.117,-13.317 -2.117,-12.488 ; -0.847,-12.488 -0.847,-12.912 -0.635,-13.317 ; 0.635,-13.317 0.847,-12.912 0.847,-12.488 ; 2.117,-13.317 2.117,-12.488 ; 3.655,-13.317 3.818,-13.099 ; 3.81,-13.123 3.81,-12.488 ; -5.08,-12.488 -5.08,-0.635 -3.81,-0.635 -3.81,0.635 -5.08,0.635 -5.08,2.752 5.08,2.752 5.08,0.635 3.81,0.635 3.81,-0.635 5.08,-0.635 5.08,-12.488 ; -5.08,-12.488 5.08,-12.488 ; -5.08,-12.488 -4.657,-12.065 ; -4.657,-12.065 -4.657,-4.868 ; -4.657,-12.065 4.657,-12.065 ; -4.657,-4.868 -5.08,-3.598 5.08,-3.598 4.657,-4.868 ; -4.657,-4.868 4.657,-4.868 ; 4.657,-12.065 4.657,-4.868 ; 4.657,-12.065 5.08,-12.488

## TO-220V [mm]
pads (3):
  oval 2.15x2.5 hole 1.15: 1(-2.54,0) 2(2.54,0) 3(0,0)
Top Overlay:
  lines w0.254: -4.812,1.125 4.808,1.125 ; -5,2.425 -4.35,-2.075 0,-2.075 4.35,-2.075 5,2.425 0,2.425 -5,2.425

## TP-.2/.4 [mm] "Trimpotentiometer liegend klein"
pads (3):
  round 2.2 hole 1.15: 1(0,0) 2(5.08,0) 3(2.54,10.16)
Top Overlay:
  circle w0.254: c2.54,5.08 r1.136
  lines w0.254: -2.032,-1.016 7.112,-1.016 7.112,6.604 ccw(c2.54,6.604) -2.032,6.604 -2.032,-1.016

## TQFP-32 [mm]
height 1.2
pads (32):
  rrect50% 1.5x0.4 smd: 1(-4.2,2.8) 2(-4.2,2) 3(-4.2,1.2) 4(-4.2,0.4) 5(-4.2,-0.4) 6(-4.2,-1.2) 7(-4.2,-2) 8(-4.2,-2.8) 17(4.2,-2.8) 18(4.2,-2) 19(4.2,-1.2) 20(4.2,-0.4) 21(4.2,0.4) 22(4.2,1.2) 23(4.2,2) 24(4.2,2.8)
  rrect50% 0.4x1.5 smd: 9(-2.8,-4.2) 10(-2,-4.2) 11(-1.2,-4.2) 12(-0.4,-4.2) 13(0.4,-4.2) 14(1.2,-4.2) 15(2,-4.2) 16(2.8,-4.2) 25(2.8,4.2) 26(2,4.2) 27(1.2,4.2) 28(0.4,4.2) 29(-0.4,4.2) 30(-1.2,4.2) 31(-2,4.2) 32(-2.8,4.2)
Top Overlay:
  circle w0.076: c-3.127,2.8 r0.127
  lines w0.076: -3.5,-3 -4.5,-3 -4.5,-2.6 -3.5,-2.6 ; -3.5,-2.2 -4.5,-2.2 ; -3.5,-1.8 -4.5,-1.8 ; -3.5,-1.4 -4.5,-1.4 ; -3.5,-1 -4.5,-1 ; -3.5,-0.6 -4.5,-0.6 ; -3.5,-0.2 -4.5,-0.2 ; -3.5,0.2 -4.5,0.2 ; -3.5,0.6 -4.5,0.6 ; -3.5,1 -4.5,1 ; -3.5,1.4 -4.5,1.4 ; -3.5,1.8 -4.5,1.8 ; -3.5,2.2 -4.5,2.2 ; -3.5,2.6 -4.5,2.6 ; -3.5,3 -4.5,3 ; -3,-3.5 -3,-4.5 -2.6,-4.5 -2.6,-3.5 ; -3,3.5 -3,4.5 -2.6,4.5 -2.6,3.5 ; -2.2,-3.5 -2.2,-4.5 ; -2.2,3.5 -2.2,4.5 ; -1.8,-3.5 -1.8,-4.5 ; -1.8,3.5 -1.8,4.5 ; -1.4,-3.5 -1.4,-4.5 ; -1.4,3.5 -1.4,4.5 ; -1,-3.5 -1,-4.5 ; -1,3.5 -1,4.5 ; -0.6,-3.5 -0.6,-4.5 ; -0.6,3.5 -0.6,4.5 ; 0.2,-3.5 0.2,-4.5 ; 0.2,3.5 0.2,4.5 ; 0.6,-3.5 0.6,-4.5 ; 0.6,3.5 0.6,4.5 ; 1,-3.5 1,-4.5 ; 1,3.5 1,4.5 ; 1.4,-3.5 1.4,-4.5 ; 1.4,3.5 1.4,4.5 ; 1.8,-3.5 1.8,-4.5 2.2,-4.5 2.2,-3.5 ; 1.8,3.5 1.8,4.5 ; 2.2,3.5 2.2,4.5 ; 2.6,-3.5 2.6,-4.5 3,-4.5 3,-3.5 ; 2.6,3.5 2.6,4.5 3,4.5 3,3.5 ; 3.5,-3 4.5,-3 ; 3.5,-2.6 4.5,-2.6 ; 3.5,-2.2 4.5,-2.2 ; 3.5,-1.8 4.5,-1.8 ; 3.5,-1.4 4.5,-1.4 ; 3.5,-1 4.5,-1 ; 3.5,-0.6 4.5,-0.6 ; 3.5,-0.2 4.5,-0.2 ; 3.5,0.2 4.5,0.2 ; 3.5,0.6 4.5,0.6 ; 3.5,1 4.5,1 ; 3.5,1.4 4.5,1.4 ; 3.5,1.8 4.5,1.8 ; 3.5,2.2 4.5,2.2 ; 3.5,2.6 4.5,2.6 4.5,3 3.5,3 ; -4.5,-2.2 -4.5,-1.8 ; -4.5,-2.2 -4.5,-1.8 ; -4.5,-1.4 -4.5,-1 ; -4.5,-1.4 -4.5,-1 ; -4.5,-0.6 -4.5,-0.2 ; -4.5,-0.6 -4.5,-0.2 ; -4.5,0.2 -4.5,0.6 ; -4.5,0.2 -4.5,0.6 ; -4.5,1 -4.5,1.4 ; -4.5,1 -4.5,1.4 ; -4.5,1.8 -4.5,2.2 ; -4.5,1.8 -4.5,2.2 ; -4.5,2.6 -4.5,3 ; -4.5,2.6 -4.5,3 ; -3.5,3.2 -3.5,-3.5 3.5,-3.5 3.5,3.5 -3.2,3.5 ; -3.5,3.2 -3.5,3.2 ; -3.5,3.2 -3.2,3.5 ; -3.5,3.2 -3.2,3.5 ; -2.2,-4.5 -1.8,-4.5 ; -2.2,-4.5 -1.8,-4.5 ; -2.2,4.5 -1.8,4.5 ; -2.2,4.5 -1.8,4.5 ; -1.4,-4.5 -1,-4.5 ; -1.4,-4.5 -1,-4.5 ; -1.4,4.5 -1,4.5 ; -1.4,4.5 -1,4.5 ; -0.6,-4.5 -0.2,-4.5 ; -0.6,-4.5 -0.2,-4.5 ; -0.6,4.5 -0.2,4.5 ; -0.6,4.5 -0.2,4.5 ; -0.2,-4.5 -0.2,-3.5 -0.2,-4.5 ; -0.2,4.5 -0.2,3.5 -0.2,4.5 ; 0.2,-4.5 0.6,-4.5 ; 0.2,-4.5 0.6,-4.5 ; 0.2,4.5 0.6,4.5 ; 0.2,4.5 0.6,4.5 ; 1,-4.5 1.4,-4.5 ; 1,-4.5 1.4,-4.5 ; 1,4.5 1.4,4.5 ; 1,4.5 1.4,4.5 ; 1.8,4.5 2.2,4.5 ; 1.8,4.5 2.2,4.5 ; 4.5,-3 4.5,-2.6 ; 4.5,-3 4.5,-2.6 ; 4.5,-2.2 4.5,-1.8 ; 4.5,-2.2 4.5,-1.8 ; 4.5,-1.4 4.5,-1 ; 4.5,-1.4 4.5,-1 ; 4.5,-0.6 4.5,-0.2 ; 4.5,-0.6 4.5,-0.2 ; 4.5,0.2 4.5,0.6 ; 4.5,0.2 4.5,0.6 ; 4.5,1 4.5,1.4 ; 4.5,1 4.5,1.4 ; 4.5,1.8 4.5,2.2 ; 4.5,1.8 4.5,2.2

## Trimm-Ko [mm]
pads (3):
  round 2.15 hole 1.15: 1(0,3.5) 2(-3.55,0) 2(3.55,0)
Top Overlay:
  circle w0.254: c0,0 r1.25
  circle w0.254: c0,0 r3.75
  lines w0.254: -0.762,-0.762 0,0 0.762,0.762

## uart [mm]
pads (24):
  round 1.85 hole 0.85: 3V3(13.208,16.764) 5V(10.668,16.764) CTS(1.778,5.08) CTS(15.748,16.764) DCD(23.368,1.016) DTR(5.588,1.016) ENTEN(20.828,16.764) GND(18.288,1.016) PWR(23.368,16.764) R1(15.748,1.016) RSD(20.828,1.016) RTS(8.128,1.016) RX(1.778,12.7) RXC(13.208,1.016) RXL(8.128,16.764) SLEEP(18.288,16.764) TX(1.778,10.16) TXL(5.588,16.764) VCC(1.778,7.62) VCC(10.668,1.016)
  oval 1.85x1.5 hole 0.85: DTR(1.778,15.24) GND(1.778,2.54) GND(3.048,16.764) TXD(3.048,1.016)
Top Overlay:
  lines w0.254: 0,0 0,18 36,18 36,0 0,0 ; 32,5 39,5 39,13 34,13 32,13 32,5

## USB-B [mm]
pads (6):
  rect 1.75x1.75 hole 0.95: 1(1.25,4.71)
  round 1.75 hole 0.95: 2(-1.25,4.71) 3(-1.25,2.71) 4(1.25,2.71)
  round 3.346 hole 2.33: P1(-6.02,0) P2(6.02,0)
Top Overlay:
  lines w0.4: -6.05,-2 -6.05,-10.3 6.05,-10.3 6.05,-2 ; -6.05,2 -6.05,6.2 6.05,6.2 6.05,2

## Verstärker 5V [mm]
pads (6):
  round 1.85 hole 0.85: 0(-6.35,0) 1(-3.81,0) 1(-1.27,0) 2(1.27,0) 3(3.81,0) 4(6.35,0)
Top Overlay:
  lines w0.254: -8.89,2.54 8.89,2.54 ; -8.89,-2.54 -8.89,0 -8.89,20.32 8.89,20.32 8.89,-2.54 -8.89,-2.54

## WM-C1610M [mm]
pads (16):
  round 1.85 hole 0.85: 1(-32,15.5) 2(-29.46,15.5) 3(-26.92,15.5) 4(-24.38,15.5) 5(-21.84,15.5) 6(-19.3,15.5) 7(-16.76,15.5) 8(-14.22,15.5) 9(-11.68,15.5) 10(-9.14,15.5) 11(-6.6,15.5) 12(-4.06,15.5) 13(-1.52,15.5) 14(1.02,15.5) 15(3.56,15.5) 16(6.1,15.5)
Top Overlay:
  circle w0.2: c-37.51,15.538 r1.25
  circle w0.2: c-37.51,-15.462 r1.25
  circle w0.2: c37.49,15.538 r1.25
  circle w0.2: c37.49,6.538 r0.5
  circle w0.2: c37.49,2.578 r0.5
  circle w0.2: c37.49,-2.502 r0.5
  circle w0.2: c37.49,-6.462 r0.5
  circle w0.2: c37.49,-15.462 r1.25
  lines w0.1: -38.75,-15.462 -36.26,-15.462 ; -38.75,15.538 -36.26,15.538 ; -37.51,-16.75 -37.51,-14.25 ; -37.51,14.25 -37.51,16.75 ; 36.25,-15.462 38.74,-15.462 ; 36.25,15.538 38.74,15.538 ; 37.49,-16.75 37.49,-14.25 ; 37.49,14.25 37.49,16.75
  lines w0.2: -33.01,15.498 -33.01,18.038 ; -31.01,15.498 -31.01,18.038 ; -30.47,15.498 -30.47,18.038 ; -28.47,15.498 -28.47,18.038 ; -27.93,15.338 -27.93,18.038 ; -25.93,15.338 -25.93,18.038 ; -25.39,15.498 -25.39,18.038 ; -23.39,15.498 -23.39,18.038 ; -22.85,15.498 -22.85,18.038 ; -20.85,15.498 -20.85,18.038 ; -20.31,15.498 -20.31,18.038 ; -18.31,15.498 -18.31,18.038 ; -17.77,15.498 -17.77,18.038 ; -15.77,15.498 -15.77,18.038 ; -15.23,15.498 -15.23,18.038 ; -13.23,15.498 -13.23,18.038 ; -12.69,15.498 -12.69,18.038 ; -10.69,15.498 -10.69,18.038 ; -10.15,15.468 -10.15,18.038 ; -8.15,15.468 -8.15,18.038 ; -7.61,15.468 -7.61,18.038 ; -5.61,15.468 -5.61,18.038 ; -5.07,15.498 -5.07,18.038 ; -3.07,15.498 -3.07,18.038 ; -2.53,15.498 -2.53,18.038 ; -0.53,15.498 -0.53,18.038 ; 0.01,15.498 0.01,18.038 ; 2.01,15.498 2.01,18.038 ; 2.55,15.498 2.55,18.038 ; 4.55,15.498 4.55,18.038 ; 5.09,15.498 5.09,18.038 ; 7.09,15.498 7.09,18.038 ; 35.59,-7.962 39.99,-7.962 ; 35.59,-4.962 39.99,-4.962 ; 35.59,-4.002 39.99,-4.002 ; 35.59,-1.002 39.99,-1.002 ; 35.59,1.078 39.99,1.078 ; 35.59,4.078 39.99,4.078 ; 35.59,5.038 39.99,5.038 ; 35.59,8.038 39.99,8.038 ; -40.01,-17.962 39.99,-17.962 39.99,18.038 -40.01,18.038 -40.01,-17.962 ; -35.61,-12.562 -35.61,12.638 35.59,12.638 35.59,-12.562 -35.61,-12.562 ; -32.24,-7.462 32.22,-7.462 32.22,7.538 -32.24,7.538 -32.24,-7.462

## XTAL SMD [mm]
pads (2):
  rect 5.5x2 smd: 1(-4.75,0) 2(4.75,0)
Top Overlay:
  lines w0.127: -5.7,-1.254 -5.7,-2.4 5.7,-2.4 5.7,-1.254 ; -5.7,1.254 -5.7,2.4 5.7,2.4 5.7,1.254
Mechanical 13:
  lines w0.127: -5.7,-2.4 5.7,-2.4 ; -5.7,2.4 5.7,2.4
